VERSION 5.7 ;
  NOWIREEXTENSIONATPIN ON ;
  DIVIDERCHAR "/" ;
  BUSBITCHARS "[]" ;
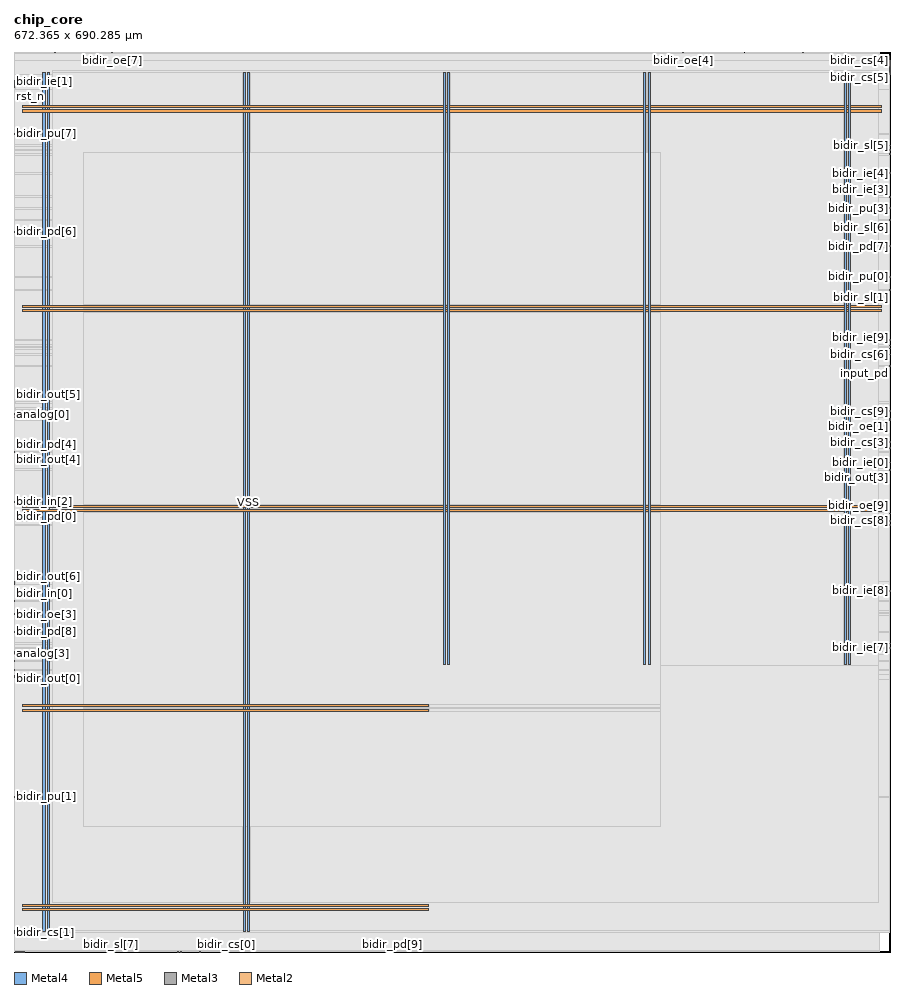
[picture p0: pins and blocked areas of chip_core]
MACRO chip_core
  CLASS BLOCK ;
  FOREIGN chip_core ;
  ORIGIN 0.000 0.000 ;
  SIZE 672.365 BY 690.285 ;
  PIN VDD
    DIRECTION INOUT ;
    USE POWER ;
    PORT
      LAYER Metal4 ;
        RECT 22.240 15.380 23.840 674.540 ;
    END
    PORT
      LAYER Metal4 ;
        RECT 175.840 15.380 177.440 674.540 ;
    END
    PORT
      LAYER Metal4 ;
        RECT 329.440 220.280 331.040 674.540 ;
    END
    PORT
      LAYER Metal4 ;
        RECT 483.040 220.280 484.640 674.540 ;
    END
    PORT
      LAYER Metal4 ;
        RECT 636.640 220.280 638.240 674.540 ;
    END
    PORT
      LAYER Metal5 ;
        RECT 6.720 31.530 318.290 33.130 ;
    END
    PORT
      LAYER Metal5 ;
        RECT 6.720 184.710 318.290 186.310 ;
    END
    PORT
      LAYER Metal5 ;
        RECT 6.720 337.890 665.280 339.490 ;
    END
    PORT
      LAYER Metal5 ;
        RECT 6.720 491.070 665.280 492.670 ;
    END
    PORT
      LAYER Metal5 ;
        RECT 6.720 644.250 665.280 645.850 ;
    END
  END VDD
  PIN VSS
    DIRECTION INOUT ;
    USE GROUND ;
    PORT
      LAYER Metal4 ;
        RECT 25.540 15.380 27.140 674.540 ;
    END
    PORT
      LAYER Metal4 ;
        RECT 179.140 15.380 180.740 674.540 ;
    END
    PORT
      LAYER Metal4 ;
        RECT 332.740 220.280 334.340 674.540 ;
    END
    PORT
      LAYER Metal4 ;
        RECT 486.340 220.280 487.940 674.540 ;
    END
    PORT
      LAYER Metal4 ;
        RECT 639.940 220.280 641.540 674.540 ;
    END
    PORT
      LAYER Metal5 ;
        RECT 6.720 34.830 318.290 36.430 ;
    END
    PORT
      LAYER Metal5 ;
        RECT 6.720 188.010 318.290 189.610 ;
    END
    PORT
      LAYER Metal5 ;
        RECT 6.720 341.190 665.280 342.790 ;
    END
    PORT
      LAYER Metal5 ;
        RECT 6.720 494.370 665.280 495.970 ;
    END
    PORT
      LAYER Metal5 ;
        RECT 6.720 647.550 665.280 649.150 ;
    END
  END VSS
  PIN analog[0]
    DIRECTION INOUT ;
    USE SIGNAL ;
    ANTENNAGATEAREA 1.017500 ;
    PORT
      LAYER Metal3 ;
        RECT 0.000 412.160 0.560 412.720 ;
    END
  END analog[0]
  PIN analog[1]
    DIRECTION INOUT ;
    USE SIGNAL ;
    ANTENNAGATEAREA 1.536500 ;
    ANTENNADIFFAREA 0.893200 ;
    PORT
      LAYER Metal3 ;
        RECT 0.000 411.040 0.560 411.600 ;
    END
  END analog[1]
  PIN analog[2]
    DIRECTION INOUT ;
    USE SIGNAL ;
    ANTENNAGATEAREA 0.894500 ;
    ANTENNADIFFAREA 0.893200 ;
    PORT
      LAYER Metal3 ;
        RECT 0.000 409.920 0.560 410.480 ;
    END
  END analog[2]
  PIN analog[3]
    DIRECTION INOUT ;
    USE SIGNAL ;
    ANTENNAGATEAREA 0.894500 ;
    ANTENNADIFFAREA 0.893200 ;
    PORT
      LAYER Metal3 ;
        RECT 0.000 228.480 0.560 229.040 ;
    END
  END analog[3]
  PIN bidir_cs[0]
    DIRECTION OUTPUT ;
    USE SIGNAL ;
    ANTENNADIFFAREA 0.536800 ;
    PORT
      LAYER Metal2 ;
        RECT 162.400 0.000 162.960 0.560 ;
    END
  END bidir_cs[0]
  PIN bidir_cs[1]
    DIRECTION OUTPUT ;
    USE SIGNAL ;
    ANTENNADIFFAREA 0.536800 ;
    PORT
      LAYER Metal3 ;
        RECT 0.000 14.560 0.560 15.120 ;
    END
  END bidir_cs[1]
  PIN bidir_cs[2]
    DIRECTION OUTPUT ;
    USE SIGNAL ;
    ANTENNADIFFAREA 0.536800 ;
    PORT
      LAYER Metal2 ;
        RECT 142.240 0.000 142.800 0.560 ;
    END
  END bidir_cs[2]
  PIN bidir_cs[3]
    DIRECTION OUTPUT ;
    USE SIGNAL ;
    ANTENNADIFFAREA 0.360800 ;
    PORT
      LAYER Metal3 ;
        RECT 671.805 390.880 672.365 391.440 ;
    END
  END bidir_cs[3]
  PIN bidir_cs[4]
    DIRECTION OUTPUT ;
    USE SIGNAL ;
    ANTENNADIFFAREA 0.360800 ;
    PORT
      LAYER Metal3 ;
        RECT 671.805 683.200 672.365 683.760 ;
    END
  END bidir_cs[4]
  PIN bidir_cs[5]
    DIRECTION OUTPUT ;
    USE SIGNAL ;
    ANTENNADIFFAREA 0.360800 ;
    PORT
      LAYER Metal3 ;
        RECT 671.805 676.480 672.365 677.040 ;
    END
  END bidir_cs[5]
  PIN bidir_cs[6]
    DIRECTION OUTPUT ;
    USE SIGNAL ;
    ANTENNADIFFAREA 0.360800 ;
    PORT
      LAYER Metal3 ;
        RECT 671.805 458.080 672.365 458.640 ;
    END
  END bidir_cs[6]
  PIN bidir_cs[7]
    DIRECTION OUTPUT ;
    USE SIGNAL ;
    ANTENNADIFFAREA 0.360800 ;
    PORT
      LAYER Metal2 ;
        RECT 125.440 0.000 126.000 0.560 ;
    END
  END bidir_cs[7]
  PIN bidir_cs[8]
    DIRECTION OUTPUT ;
    USE SIGNAL ;
    ANTENNADIFFAREA 0.360800 ;
    PORT
      LAYER Metal3 ;
        RECT 671.805 330.400 672.365 330.960 ;
    END
  END bidir_cs[8]
  PIN bidir_cs[9]
    DIRECTION OUTPUT ;
    USE SIGNAL ;
    ANTENNADIFFAREA 0.360800 ;
    PORT
      LAYER Metal3 ;
        RECT 671.805 414.400 672.365 414.960 ;
    END
  END bidir_cs[9]
  PIN bidir_ie[0]
    DIRECTION OUTPUT ;
    USE SIGNAL ;
    ANTENNADIFFAREA 0.536800 ;
    PORT
      LAYER Metal3 ;
        RECT 671.805 375.200 672.365 375.760 ;
    END
  END bidir_ie[0]
  PIN bidir_ie[1]
    DIRECTION OUTPUT ;
    USE SIGNAL ;
    ANTENNADIFFAREA 0.536800 ;
    PORT
      LAYER Metal3 ;
        RECT 0.000 667.520 0.560 668.080 ;
    END
  END bidir_ie[1]
  PIN bidir_ie[2]
    DIRECTION OUTPUT ;
    USE SIGNAL ;
    ANTENNADIFFAREA 0.536800 ;
    PORT
      LAYER Metal3 ;
        RECT 671.805 386.400 672.365 386.960 ;
    END
  END bidir_ie[2]
  PIN bidir_ie[3]
    DIRECTION OUTPUT ;
    USE SIGNAL ;
    ANTENNADIFFAREA 0.360800 ;
    PORT
      LAYER Metal3 ;
        RECT 671.805 579.040 672.365 579.600 ;
    END
  END bidir_ie[3]
  PIN bidir_ie[4]
    DIRECTION OUTPUT ;
    USE SIGNAL ;
    ANTENNADIFFAREA 0.360800 ;
    PORT
      LAYER Metal3 ;
        RECT 671.805 596.960 672.365 597.520 ;
    END
  END bidir_ie[4]
  PIN bidir_ie[5]
    DIRECTION OUTPUT ;
    USE SIGNAL ;
    ANTENNADIFFAREA 0.360800 ;
    PORT
      LAYER Metal3 ;
        RECT 671.805 678.720 672.365 679.280 ;
    END
  END bidir_ie[5]
  PIN bidir_ie[6]
    DIRECTION OUTPUT ;
    USE SIGNAL ;
    ANTENNADIFFAREA 0.360800 ;
    PORT
      LAYER Metal3 ;
        RECT 671.805 674.240 672.365 674.800 ;
    END
  END bidir_ie[6]
  PIN bidir_ie[7]
    DIRECTION OUTPUT ;
    USE SIGNAL ;
    ANTENNADIFFAREA 0.360800 ;
    PORT
      LAYER Metal3 ;
        RECT 671.805 232.960 672.365 233.520 ;
    END
  END bidir_ie[7]
  PIN bidir_ie[8]
    DIRECTION OUTPUT ;
    USE SIGNAL ;
    ANTENNADIFFAREA 0.360800 ;
    PORT
      LAYER Metal3 ;
        RECT 671.805 276.640 672.365 277.200 ;
    END
  END bidir_ie[8]
  PIN bidir_ie[9]
    DIRECTION OUTPUT ;
    USE SIGNAL ;
    ANTENNADIFFAREA 0.360800 ;
    PORT
      LAYER Metal3 ;
        RECT 671.805 464.800 672.365 465.360 ;
    END
  END bidir_ie[9]
  PIN bidir_in[0]
    DIRECTION INPUT ;
    USE SIGNAL ;
    ANTENNAGATEAREA 0.498500 ;
    PORT
      LAYER Metal3 ;
        RECT 0.000 268.800 0.560 269.360 ;
    END
  END bidir_in[0]
  PIN bidir_in[1]
    DIRECTION INPUT ;
    USE SIGNAL ;
    ANTENNAGATEAREA 0.498500 ;
    PORT
      LAYER Metal3 ;
        RECT 0.000 260.960 0.560 261.520 ;
    END
  END bidir_in[1]
  PIN bidir_in[2]
    DIRECTION INPUT ;
    USE SIGNAL ;
    ANTENNAGATEAREA 0.498500 ;
    PORT
      LAYER Metal3 ;
        RECT 0.000 344.960 0.560 345.520 ;
    END
  END bidir_in[2]
  PIN bidir_in[3]
    DIRECTION INPUT ;
    USE SIGNAL ;
    PORT
      LAYER Metal2 ;
        RECT 1.120 0.000 1.680 0.560 ;
    END
  END bidir_in[3]
  PIN bidir_in[4]
    DIRECTION INPUT ;
    USE SIGNAL ;
    PORT
      LAYER Metal2 ;
        RECT 2.240 0.000 2.800 0.560 ;
    END
  END bidir_in[4]
  PIN bidir_in[5]
    DIRECTION INPUT ;
    USE SIGNAL ;
    PORT
      LAYER Metal2 ;
        RECT 3.360 0.000 3.920 0.560 ;
    END
  END bidir_in[5]
  PIN bidir_in[6]
    DIRECTION INPUT ;
    USE SIGNAL ;
    PORT
      LAYER Metal2 ;
        RECT 4.480 0.000 5.040 0.560 ;
    END
  END bidir_in[6]
  PIN bidir_in[7]
    DIRECTION INPUT ;
    USE SIGNAL ;
    PORT
      LAYER Metal2 ;
        RECT 5.600 0.000 6.160 0.560 ;
    END
  END bidir_in[7]
  PIN bidir_in[8]
    DIRECTION INPUT ;
    USE SIGNAL ;
    PORT
      LAYER Metal2 ;
        RECT 6.720 0.000 7.280 0.560 ;
    END
  END bidir_in[8]
  PIN bidir_in[9]
    DIRECTION INPUT ;
    USE SIGNAL ;
    PORT
      LAYER Metal2 ;
        RECT 7.840 0.000 8.400 0.560 ;
    END
  END bidir_in[9]
  PIN bidir_oe[0]
    DIRECTION OUTPUT ;
    USE SIGNAL ;
    ANTENNADIFFAREA 0.360800 ;
    PORT
      LAYER Metal3 ;
        RECT 671.805 673.120 672.365 673.680 ;
    END
  END bidir_oe[0]
  PIN bidir_oe[1]
    DIRECTION OUTPUT ;
    USE SIGNAL ;
    ANTENNADIFFAREA 0.360800 ;
    PORT
      LAYER Metal3 ;
        RECT 671.805 408.800 672.365 409.360 ;
    END
  END bidir_oe[1]
  PIN bidir_oe[2]
    DIRECTION OUTPUT ;
    USE SIGNAL ;
    ANTENNADIFFAREA 0.360800 ;
    PORT
      LAYER Metal3 ;
        RECT 671.805 611.520 672.365 612.080 ;
    END
  END bidir_oe[2]
  PIN bidir_oe[3]
    DIRECTION OUTPUT ;
    USE SIGNAL ;
    ANTENNADIFFAREA 0.897600 ;
    PORT
      LAYER Metal3 ;
        RECT 0.000 258.720 0.560 259.280 ;
    END
  END bidir_oe[3]
  PIN bidir_oe[4]
    DIRECTION OUTPUT ;
    USE SIGNAL ;
    ANTENNADIFFAREA 0.536800 ;
    PORT
      LAYER Metal2 ;
        RECT 512.960 689.725 513.520 690.285 ;
    END
  END bidir_oe[4]
  PIN bidir_oe[5]
    DIRECTION OUTPUT ;
    USE SIGNAL ;
    ANTENNADIFFAREA 0.536800 ;
    PORT
      LAYER Metal3 ;
        RECT 0.000 666.400 0.560 666.960 ;
    END
  END bidir_oe[5]
  PIN bidir_oe[6]
    DIRECTION OUTPUT ;
    USE SIGNAL ;
    ANTENNADIFFAREA 0.536800 ;
    PORT
      LAYER Metal3 ;
        RECT 671.805 614.880 672.365 615.440 ;
    END
  END bidir_oe[6]
  PIN bidir_oe[7]
    DIRECTION OUTPUT ;
    USE SIGNAL ;
    ANTENNADIFFAREA 0.536800 ;
    PORT
      LAYER Metal2 ;
        RECT 75.040 689.725 75.600 690.285 ;
    END
  END bidir_oe[7]
  PIN bidir_oe[8]
    DIRECTION OUTPUT ;
    USE SIGNAL ;
    ANTENNADIFFAREA 0.536800 ;
    PORT
      LAYER Metal3 ;
        RECT 671.805 236.320 672.365 236.880 ;
    END
  END bidir_oe[8]
  PIN bidir_oe[9]
    DIRECTION OUTPUT ;
    USE SIGNAL ;
    ANTENNADIFFAREA 0.536800 ;
    PORT
      LAYER Metal3 ;
        RECT 671.805 336.000 672.365 336.560 ;
    END
  END bidir_oe[9]
  PIN bidir_out[0]
    DIRECTION OUTPUT ;
    USE SIGNAL ;
    ANTENNADIFFAREA 0.897600 ;
    PORT
      LAYER Metal3 ;
        RECT 0.000 209.440 0.560 210.000 ;
    END
  END bidir_out[0]
  PIN bidir_out[1]
    DIRECTION OUTPUT ;
    USE SIGNAL ;
    ANTENNADIFFAREA 0.897600 ;
    PORT
      LAYER Metal3 ;
        RECT 0.000 211.680 0.560 212.240 ;
    END
  END bidir_out[1]
  PIN bidir_out[2]
    DIRECTION OUTPUT ;
    USE SIGNAL ;
    ANTENNADIFFAREA 0.897600 ;
    PORT
      LAYER Metal3 ;
        RECT 0.000 216.160 0.560 216.720 ;
    END
  END bidir_out[2]
  PIN bidir_out[3]
    DIRECTION OUTPUT ;
    USE SIGNAL ;
    ANTENNADIFFAREA 0.897600 ;
    PORT
      LAYER Metal3 ;
        RECT 671.805 369.600 672.365 370.160 ;
    END
  END bidir_out[3]
  PIN bidir_out[4]
    DIRECTION OUTPUT ;
    USE SIGNAL ;
    ANTENNADIFFAREA 0.897600 ;
    PORT
      LAYER Metal3 ;
        RECT 0.000 377.440 0.560 378.000 ;
    END
  END bidir_out[4]
  PIN bidir_out[5]
    DIRECTION OUTPUT ;
    USE SIGNAL ;
    ANTENNADIFFAREA 0.897600 ;
    PORT
      LAYER Metal3 ;
        RECT 0.000 421.120 0.560 421.680 ;
    END
  END bidir_out[5]
  PIN bidir_out[6]
    DIRECTION OUTPUT ;
    USE SIGNAL ;
    ANTENNADIFFAREA 0.897600 ;
    PORT
      LAYER Metal3 ;
        RECT 0.000 282.240 0.560 282.800 ;
    END
  END bidir_out[6]
  PIN bidir_out[7]
    DIRECTION OUTPUT ;
    USE SIGNAL ;
    ANTENNADIFFAREA 0.897600 ;
    PORT
      LAYER Metal3 ;
        RECT 0.000 283.360 0.560 283.920 ;
    END
  END bidir_out[7]
  PIN bidir_out[8]
    DIRECTION OUTPUT ;
    USE SIGNAL ;
    ANTENNADIFFAREA 0.897600 ;
    PORT
      LAYER Metal3 ;
        RECT 0.000 416.640 0.560 417.200 ;
    END
  END bidir_out[8]
  PIN bidir_out[9]
    DIRECTION OUTPUT ;
    USE SIGNAL ;
    ANTENNADIFFAREA 0.897600 ;
    PORT
      LAYER Metal3 ;
        RECT 0.000 229.600 0.560 230.160 ;
    END
  END bidir_out[9]
  PIN bidir_pd[0]
    DIRECTION OUTPUT ;
    USE SIGNAL ;
    ANTENNADIFFAREA 0.360800 ;
    PORT
      LAYER Metal3 ;
        RECT 0.000 333.760 0.560 334.320 ;
    END
  END bidir_pd[0]
  PIN bidir_pd[1]
    DIRECTION OUTPUT ;
    USE SIGNAL ;
    ANTENNADIFFAREA 0.360800 ;
    PORT
      LAYER Metal3 ;
        RECT 671.805 679.840 672.365 680.400 ;
    END
  END bidir_pd[1]
  PIN bidir_pd[2]
    DIRECTION OUTPUT ;
    USE SIGNAL ;
    ANTENNADIFFAREA 0.360800 ;
    PORT
      LAYER Metal3 ;
        RECT 671.805 675.360 672.365 675.920 ;
    END
  END bidir_pd[2]
  PIN bidir_pd[3]
    DIRECTION OUTPUT ;
    USE SIGNAL ;
    ANTENNADIFFAREA 0.360800 ;
    PORT
      LAYER Metal3 ;
        RECT 671.805 462.560 672.365 463.120 ;
    END
  END bidir_pd[3]
  PIN bidir_pd[4]
    DIRECTION OUTPUT ;
    USE SIGNAL ;
    ANTENNADIFFAREA 0.360800 ;
    PORT
      LAYER Metal3 ;
        RECT 0.000 383.040 0.560 383.600 ;
    END
  END bidir_pd[4]
  PIN bidir_pd[5]
    DIRECTION OUTPUT ;
    USE SIGNAL ;
    ANTENNADIFFAREA 0.360800 ;
    PORT
      LAYER Metal2 ;
        RECT 31.360 689.725 31.920 690.285 ;
    END
  END bidir_pd[5]
  PIN bidir_pd[6]
    DIRECTION OUTPUT ;
    USE SIGNAL ;
    ANTENNADIFFAREA 0.360800 ;
    PORT
      LAYER Metal3 ;
        RECT 0.000 552.160 0.560 552.720 ;
    END
  END bidir_pd[6]
  PIN bidir_pd[7]
    DIRECTION OUTPUT ;
    USE SIGNAL ;
    ANTENNADIFFAREA 0.360800 ;
    PORT
      LAYER Metal3 ;
        RECT 671.805 540.960 672.365 541.520 ;
    END
  END bidir_pd[7]
  PIN bidir_pd[8]
    DIRECTION OUTPUT ;
    USE SIGNAL ;
    ANTENNADIFFAREA 0.360800 ;
    PORT
      LAYER Metal3 ;
        RECT 0.000 245.280 0.560 245.840 ;
    END
  END bidir_pd[8]
  PIN bidir_pd[9]
    DIRECTION OUTPUT ;
    USE SIGNAL ;
    ANTENNADIFFAREA 0.360800 ;
    PORT
      LAYER Metal2 ;
        RECT 290.080 0.000 290.640 0.560 ;
    END
  END bidir_pd[9]
  PIN bidir_pu[0]
    DIRECTION OUTPUT ;
    USE SIGNAL ;
    ANTENNADIFFAREA 0.536800 ;
    PORT
      LAYER Metal3 ;
        RECT 671.805 517.440 672.365 518.000 ;
    END
  END bidir_pu[0]
  PIN bidir_pu[1]
    DIRECTION OUTPUT ;
    USE SIGNAL ;
    ANTENNADIFFAREA 0.360800 ;
    PORT
      LAYER Metal3 ;
        RECT 0.000 118.720 0.560 119.280 ;
    END
  END bidir_pu[1]
  PIN bidir_pu[2]
    DIRECTION OUTPUT ;
    USE SIGNAL ;
    ANTENNADIFFAREA 0.360800 ;
    PORT
      LAYER Metal3 ;
        RECT 671.805 327.040 672.365 327.600 ;
    END
  END bidir_pu[2]
  PIN bidir_pu[3]
    DIRECTION OUTPUT ;
    USE SIGNAL ;
    ANTENNADIFFAREA 0.360800 ;
    PORT
      LAYER Metal3 ;
        RECT 671.805 570.080 672.365 570.640 ;
    END
  END bidir_pu[3]
  PIN bidir_pu[4]
    DIRECTION OUTPUT ;
    USE SIGNAL ;
    ANTENNADIFFAREA 0.360800 ;
    PORT
      LAYER Metal3 ;
        RECT 0.000 664.160 0.560 664.720 ;
    END
  END bidir_pu[4]
  PIN bidir_pu[5]
    DIRECTION OUTPUT ;
    USE SIGNAL ;
    ANTENNADIFFAREA 0.360800 ;
    PORT
      LAYER Metal3 ;
        RECT 671.805 680.960 672.365 681.520 ;
    END
  END bidir_pu[5]
  PIN bidir_pu[6]
    DIRECTION OUTPUT ;
    USE SIGNAL ;
    ANTENNADIFFAREA 0.360800 ;
    PORT
      LAYER Metal3 ;
        RECT 671.805 682.080 672.365 682.640 ;
    END
  END bidir_pu[6]
  PIN bidir_pu[7]
    DIRECTION OUTPUT ;
    USE SIGNAL ;
    ANTENNADIFFAREA 0.360800 ;
    PORT
      LAYER Metal3 ;
        RECT 0.000 627.200 0.560 627.760 ;
    END
  END bidir_pu[7]
  PIN bidir_pu[8]
    DIRECTION OUTPUT ;
    USE SIGNAL ;
    ANTENNADIFFAREA 0.360800 ;
    PORT
      LAYER Metal3 ;
        RECT 0.000 15.680 0.560 16.240 ;
    END
  END bidir_pu[8]
  PIN bidir_pu[9]
    DIRECTION OUTPUT ;
    USE SIGNAL ;
    ANTENNADIFFAREA 0.360800 ;
    PORT
      LAYER Metal3 ;
        RECT 671.805 469.280 672.365 469.840 ;
    END
  END bidir_pu[9]
  PIN bidir_sl[0]
    DIRECTION OUTPUT ;
    USE SIGNAL ;
    ANTENNADIFFAREA 0.360800 ;
    PORT
      LAYER Metal3 ;
        RECT 0.000 222.880 0.560 223.440 ;
    END
  END bidir_sl[0]
  PIN bidir_sl[1]
    DIRECTION OUTPUT ;
    USE SIGNAL ;
    ANTENNADIFFAREA 0.360800 ;
    PORT
      LAYER Metal3 ;
        RECT 671.805 507.360 672.365 507.920 ;
    END
  END bidir_sl[1]
  PIN bidir_sl[2]
    DIRECTION OUTPUT ;
    USE SIGNAL ;
    ANTENNADIFFAREA 0.360800 ;
    PORT
      LAYER Metal2 ;
        RECT 560.000 689.725 560.560 690.285 ;
    END
  END bidir_sl[2]
  PIN bidir_sl[3]
    DIRECTION OUTPUT ;
    USE SIGNAL ;
    ANTENNADIFFAREA 0.536800 ;
    PORT
      LAYER Metal3 ;
        RECT 671.805 407.680 672.365 408.240 ;
    END
  END bidir_sl[3]
  PIN bidir_sl[4]
    DIRECTION OUTPUT ;
    USE SIGNAL ;
    ANTENNADIFFAREA 0.360800 ;
    PORT
      LAYER Metal3 ;
        RECT 0.000 665.280 0.560 665.840 ;
    END
  END bidir_sl[4]
  PIN bidir_sl[5]
    DIRECTION OUTPUT ;
    USE SIGNAL ;
    ANTENNADIFFAREA 0.360800 ;
    PORT
      LAYER Metal3 ;
        RECT 671.805 618.240 672.365 618.800 ;
    END
  END bidir_sl[5]
  PIN bidir_sl[6]
    DIRECTION OUTPUT ;
    USE SIGNAL ;
    ANTENNADIFFAREA 0.360800 ;
    PORT
      LAYER Metal3 ;
        RECT 671.805 561.120 672.365 561.680 ;
    END
  END bidir_sl[6]
  PIN bidir_sl[7]
    DIRECTION OUTPUT ;
    USE SIGNAL ;
    ANTENNADIFFAREA 0.360800 ;
    PORT
      LAYER Metal2 ;
        RECT 73.920 0.000 74.480 0.560 ;
    END
  END bidir_sl[7]
  PIN bidir_sl[8]
    DIRECTION OUTPUT ;
    USE SIGNAL ;
    ANTENNADIFFAREA 0.360800 ;
    PORT
      LAYER Metal3 ;
        RECT 671.805 677.600 672.365 678.160 ;
    END
  END bidir_sl[8]
  PIN bidir_sl[9]
    DIRECTION OUTPUT ;
    USE SIGNAL ;
    ANTENNADIFFAREA 0.360800 ;
    PORT
      LAYER Metal2 ;
        RECT 604.800 689.725 605.360 690.285 ;
    END
  END bidir_sl[9]
  PIN clk
    DIRECTION INPUT ;
    USE SIGNAL ;
    ANTENNAGATEAREA 4.738000 ;
    PORT
      LAYER Metal3 ;
        RECT 0.000 663.040 0.560 663.600 ;
    END
  END clk
  PIN input_in
    DIRECTION INPUT ;
    USE SIGNAL ;
    ANTENNAGATEAREA 0.498500 ;
    PORT
      LAYER Metal3 ;
        RECT 0.000 210.560 0.560 211.120 ;
    END
  END input_in
  PIN input_pd
    DIRECTION OUTPUT ;
    USE SIGNAL ;
    ANTENNADIFFAREA 0.360800 ;
    PORT
      LAYER Metal3 ;
        RECT 671.805 449.120 672.365 449.680 ;
    END
  END input_pd
  PIN input_pu
    DIRECTION OUTPUT ;
    USE SIGNAL ;
    ANTENNADIFFAREA 0.360800 ;
    PORT
      LAYER Metal2 ;
        RECT 127.680 0.000 128.240 0.560 ;
    END
  END input_pu
  PIN rst_n
    DIRECTION INPUT ;
    USE SIGNAL ;
    ANTENNAGATEAREA 0.498500 ;
    PORT
      LAYER Metal3 ;
        RECT 0.000 661.920 0.560 662.480 ;
    END
  END rst_n
  OBS
      LAYER Nwell ;
        RECT 6.290 15.250 665.710 674.670 ;
      LAYER Metal1 ;
        RECT 6.720 15.380 665.280 674.540 ;
      LAYER Metal2 ;
        RECT 0.140 689.425 31.060 689.725 ;
        RECT 32.220 689.425 74.740 689.725 ;
        RECT 75.900 689.425 512.660 689.725 ;
        RECT 513.820 689.425 559.700 689.725 ;
        RECT 560.860 689.425 604.500 689.725 ;
        RECT 605.660 689.425 664.020 689.725 ;
        RECT 0.140 0.860 664.020 689.425 ;
        RECT 0.140 0.560 0.820 0.860 ;
        RECT 8.700 0.560 73.620 0.860 ;
        RECT 74.780 0.560 125.140 0.860 ;
        RECT 126.300 0.560 127.380 0.860 ;
        RECT 128.540 0.560 141.940 0.860 ;
        RECT 143.100 0.560 162.100 0.860 ;
        RECT 163.260 0.560 289.780 0.860 ;
        RECT 290.940 0.560 664.020 0.860 ;
      LAYER Metal3 ;
        RECT 0.090 672.820 671.505 683.620 ;
        RECT 0.090 668.380 671.805 672.820 ;
        RECT 0.860 661.620 671.805 668.380 ;
        RECT 0.090 628.060 671.805 661.620 ;
        RECT 0.860 626.900 671.805 628.060 ;
        RECT 0.090 619.100 671.805 626.900 ;
        RECT 0.090 617.940 671.505 619.100 ;
        RECT 0.090 615.740 671.805 617.940 ;
        RECT 0.090 614.580 671.505 615.740 ;
        RECT 0.090 612.380 671.805 614.580 ;
        RECT 0.090 611.220 671.505 612.380 ;
        RECT 0.090 597.820 671.805 611.220 ;
        RECT 0.090 596.660 671.505 597.820 ;
        RECT 0.090 579.900 671.805 596.660 ;
        RECT 0.090 578.740 671.505 579.900 ;
        RECT 0.090 570.940 671.805 578.740 ;
        RECT 0.090 569.780 671.505 570.940 ;
        RECT 0.090 561.980 671.805 569.780 ;
        RECT 0.090 560.820 671.505 561.980 ;
        RECT 0.090 553.020 671.805 560.820 ;
        RECT 0.860 551.860 671.805 553.020 ;
        RECT 0.090 541.820 671.805 551.860 ;
        RECT 0.090 540.660 671.505 541.820 ;
        RECT 0.090 518.300 671.805 540.660 ;
        RECT 0.090 517.140 671.505 518.300 ;
        RECT 0.090 508.220 671.805 517.140 ;
        RECT 0.090 507.060 671.505 508.220 ;
        RECT 0.090 470.140 671.805 507.060 ;
        RECT 0.090 468.980 671.505 470.140 ;
        RECT 0.090 465.660 671.805 468.980 ;
        RECT 0.090 464.500 671.505 465.660 ;
        RECT 0.090 463.420 671.805 464.500 ;
        RECT 0.090 462.260 671.505 463.420 ;
        RECT 0.090 458.940 671.805 462.260 ;
        RECT 0.090 457.780 671.505 458.940 ;
        RECT 0.090 449.980 671.805 457.780 ;
        RECT 0.090 448.820 671.505 449.980 ;
        RECT 0.090 421.980 671.805 448.820 ;
        RECT 0.860 420.820 671.805 421.980 ;
        RECT 0.090 417.500 671.805 420.820 ;
        RECT 0.860 416.340 671.805 417.500 ;
        RECT 0.090 415.260 671.805 416.340 ;
        RECT 0.090 414.100 671.505 415.260 ;
        RECT 0.090 413.020 671.805 414.100 ;
        RECT 0.860 409.660 671.805 413.020 ;
        RECT 0.860 409.620 671.505 409.660 ;
        RECT 0.090 407.380 671.505 409.620 ;
        RECT 0.090 391.740 671.805 407.380 ;
        RECT 0.090 390.580 671.505 391.740 ;
        RECT 0.090 387.260 671.805 390.580 ;
        RECT 0.090 386.100 671.505 387.260 ;
        RECT 0.090 383.900 671.805 386.100 ;
        RECT 0.860 382.740 671.805 383.900 ;
        RECT 0.090 378.300 671.805 382.740 ;
        RECT 0.860 377.140 671.805 378.300 ;
        RECT 0.090 376.060 671.805 377.140 ;
        RECT 0.090 374.900 671.505 376.060 ;
        RECT 0.090 370.460 671.805 374.900 ;
        RECT 0.090 369.300 671.505 370.460 ;
        RECT 0.090 345.820 671.805 369.300 ;
        RECT 0.860 344.660 671.805 345.820 ;
        RECT 0.090 336.860 671.805 344.660 ;
        RECT 0.090 335.700 671.505 336.860 ;
        RECT 0.090 334.620 671.805 335.700 ;
        RECT 0.860 333.460 671.805 334.620 ;
        RECT 0.090 331.260 671.805 333.460 ;
        RECT 0.090 330.100 671.505 331.260 ;
        RECT 0.090 327.900 671.805 330.100 ;
        RECT 0.090 326.740 671.505 327.900 ;
        RECT 0.090 284.220 671.805 326.740 ;
        RECT 0.860 281.940 671.805 284.220 ;
        RECT 0.090 277.500 671.805 281.940 ;
        RECT 0.090 276.340 671.505 277.500 ;
        RECT 0.090 269.660 671.805 276.340 ;
        RECT 0.860 268.500 671.805 269.660 ;
        RECT 0.090 261.820 671.805 268.500 ;
        RECT 0.860 260.660 671.805 261.820 ;
        RECT 0.090 259.580 671.805 260.660 ;
        RECT 0.860 258.420 671.805 259.580 ;
        RECT 0.090 246.140 671.805 258.420 ;
        RECT 0.860 244.980 671.805 246.140 ;
        RECT 0.090 237.180 671.805 244.980 ;
        RECT 0.090 236.020 671.505 237.180 ;
        RECT 0.090 233.820 671.805 236.020 ;
        RECT 0.090 232.660 671.505 233.820 ;
        RECT 0.090 230.460 671.805 232.660 ;
        RECT 0.860 228.180 671.805 230.460 ;
        RECT 0.090 223.740 671.805 228.180 ;
        RECT 0.860 222.580 671.805 223.740 ;
        RECT 0.090 217.020 671.805 222.580 ;
        RECT 0.860 215.860 671.805 217.020 ;
        RECT 0.090 212.540 671.805 215.860 ;
        RECT 0.860 209.140 671.805 212.540 ;
        RECT 0.090 119.580 671.805 209.140 ;
        RECT 0.860 118.420 671.805 119.580 ;
        RECT 0.090 16.540 671.805 118.420 ;
        RECT 0.860 14.700 671.805 16.540 ;
      LAYER Metal4 ;
        RECT 29.820 674.840 662.900 675.830 ;
        RECT 29.820 38.170 175.540 674.840 ;
        RECT 177.740 38.170 178.840 674.840 ;
        RECT 181.040 219.980 329.140 674.840 ;
        RECT 331.340 219.980 332.440 674.840 ;
        RECT 334.640 219.980 482.740 674.840 ;
        RECT 484.940 219.980 486.040 674.840 ;
        RECT 488.240 219.980 636.340 674.840 ;
        RECT 638.540 219.980 639.640 674.840 ;
        RECT 641.840 219.980 662.900 674.840 ;
        RECT 181.040 38.170 662.900 219.980 ;
      LAYER Metal5 ;
        RECT 53.260 496.570 496.100 613.570 ;
        RECT 53.260 493.270 496.100 493.770 ;
        RECT 53.260 343.390 496.100 490.470 ;
        RECT 53.260 340.090 496.100 340.590 ;
        RECT 53.260 190.210 496.100 337.290 ;
        RECT 318.890 187.410 496.100 190.210 ;
        RECT 53.260 186.910 496.100 187.410 ;
        RECT 318.890 184.110 496.100 186.910 ;
        RECT 53.260 96.530 496.100 184.110 ;
  END
END chip_core
END LIBRARY

